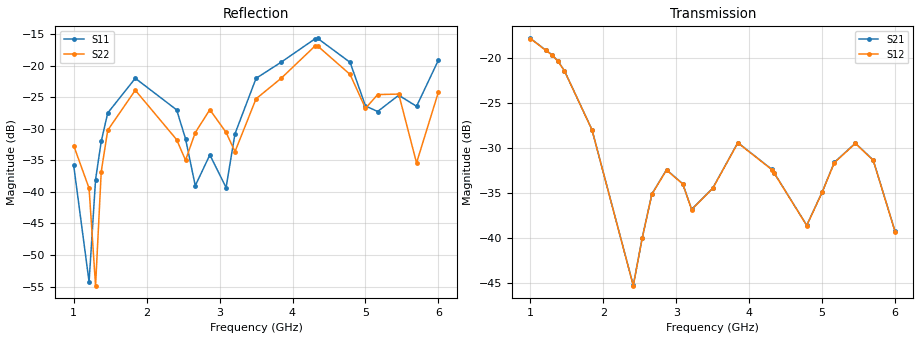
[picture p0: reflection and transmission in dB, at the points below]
!Agilent Technologies,E8364B,MY43040528,A.07.50.67
!Agilent E8364B: A.07.50.67
!Date: Sunday, March 01, 2026 23:16:00
!Correction: S11(Full 2 Port(1,2))
!S21(Full 2 Port(1,2))
!S12(Full 2 Port(1,2))
!S22(Full 2 Port(1,2))
!S2P File: Measurements: S11, S21, S12, S22:
# Hz S  dB  R 50
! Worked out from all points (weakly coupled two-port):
!   451 points, 1 GHz to 6 GHz, reference 50 ohm
!   highest |S21| = -17.84 dB at 1 GHz (marker M1); lowest = -45.2 dB at 2.411 GHz (marker M2)
!   lowest |S11| = -54.3 dB at 1.211 GHz (marker M3), VSWR 1.00, Z = 50.1 - j0.182 ohm
!   |S11| at or under -10 dB: start of sweep to end of sweep
!   |S22| runs from -54.9 to -16.9 dB; largest |S21 - S12| = 0.00045
!   S11 on the Smith chart (normalised r, x): 1 GHz: 1.03, +0.01; 4.311 GHz: 1.22, -0.29; 6 GHz: 0.96, -0.21
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1e9  -35.81 10.2  -17.84 29.2  -17.87 29.2  -32.67 -12.2
1.211111e9  -54.26 -69.6  -19.14 -34.4  -19.17 -34.4  -39.44 -29.3
1.3e9  -38.06 -154.6  -19.68 -63.6  -19.71 -63.5  -54.86 -142.5
1.377778e9  -32.00 -175.2  -20.36 -89.8  -20.39 -89.7  -36.80 119.1
1.466667e9  -27.52 159.9  -21.42 -119.7  -21.44 -119.7  -30.25 90.2
1.844444e9  -22.02 78.1  -27.96 120.7  -27.98 120.7  -23.91 -8.9
2.411111e9  -27.02 -11.3  -45.24 -123.7  -45.28 -123.9  -31.73 -97.0
2.533333e9  -31.59 -26.2  -39.98 131.6  -40.02 131.6  -34.99 -77.5
2.666667e9  -39.03 3.5  -35.09 66.1  -35.12 66.1  -30.62 -63.7
2.866667e9  -34.15 32.0  -32.42 -15.9  -32.46 -15.9  -26.99 -101.3
3.088889e9  -39.32 69.3  -33.97 -96.7  -34.00 -96.8  -30.58 -141.1
3.211111e9  -30.81 94.0  -36.81 -128.3  -36.84 -128.2  -33.64 -123.5
3.5e9  -22.03 52.3  -34.46 -155.4  -34.49 -155.4  -25.27 -129.5
3.844444e9  -19.47 15.6  -29.41 86.3  -29.44 86.3  -22.02 -164.3
4.311111e9  -15.75 -46.0  -32.38 -83.1  -32.41 -83.1  -16.88 118.0
4.344444e9  -15.70 -51.1  -32.79 -95.0  -32.82 -95.0  -16.91 111.6
4.788889e9  -19.50 -119.1  -38.58 56.5  -38.61 56.5  -21.41 30.5
5e9  -26.40 -130.2  -34.89 -72.0  -34.92 -72.1  -26.78 28.7
5.166667e9  -27.28 -92.9  -31.60 -153.6  -31.64 -153.6  -24.60 34.2
5.455556e9  -24.70 -109.8  -29.47 80.0  -29.50 80.0  -24.52 -20.9
5.7e9  -26.46 -83.6  -31.34 -20.7  -31.37 -20.8  -35.42 -13.1
6e9  -19.14 -94.1  -39.26 -116.6  -39.30 -116.7  -24.19 -3.9
